VERSION 5.7 ;
BUSBITCHARS "[]" ;
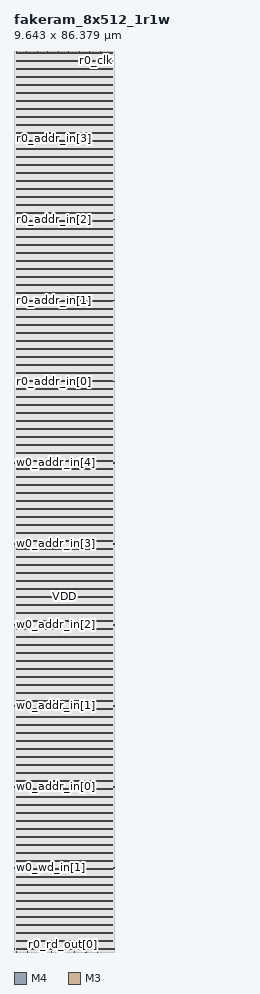
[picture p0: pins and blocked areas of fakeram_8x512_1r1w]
MACRO fakeram_8x512_1r1w
  FOREIGN fakeram_8x512_1r1w 0 0 ;
  SYMMETRY X Y R90 ;
  SIZE 9.643 BY 86.379 ;
  CLASS BLOCK ;
  PIN w0_wd_in[0]
    DIRECTION INPUT ;
    USE SIGNAL ;
    SHAPE ABUTMENT ;
    PORT
      LAYER M4 ;
      RECT 0.000 0.276 0.072 0.300 ;
    END
  END w0_wd_in[0]
  PIN w0_wd_in[1]
    DIRECTION INPUT ;
    USE SIGNAL ;
    SHAPE ABUTMENT ;
    PORT
      LAYER M4 ;
      RECT 0.000 8.052 0.072 8.076 ;
    END
  END w0_wd_in[1]
  PIN w0_wd_in[2]
    DIRECTION INPUT ;
    USE SIGNAL ;
    SHAPE ABUTMENT ;
    PORT
      LAYER M4 ;
      RECT 9.571 0.276 9.643 0.300 ;
    END
  END w0_wd_in[2]
  PIN w0_wd_in[3]
    DIRECTION INPUT ;
    USE SIGNAL ;
    SHAPE ABUTMENT ;
    PORT
      LAYER M4 ;
      RECT 9.571 8.052 9.643 8.076 ;
    END
  END w0_wd_in[3]
  PIN w0_wd_in[4]
    DIRECTION OUTPUT ;
    USE SIGNAL ;
    SHAPE ABUTMENT ;
    PORT
      LAYER M3 ;
      RECT 0.207 0.000 0.225 0.054 ;
    END
  END w0_wd_in[4]
  PIN w0_wd_in[5]
    DIRECTION OUTPUT ;
    USE SIGNAL ;
    SHAPE ABUTMENT ;
    PORT
      LAYER M3 ;
      RECT 1.323 0.000 1.341 0.054 ;
    END
  END w0_wd_in[5]
  PIN w0_wd_in[6]
    DIRECTION OUTPUT ;
    USE SIGNAL ;
    SHAPE ABUTMENT ;
    PORT
      LAYER M3 ;
      RECT 2.439 0.000 2.457 0.054 ;
    END
  END w0_wd_in[6]
  PIN w0_wd_in[7]
    DIRECTION OUTPUT ;
    USE SIGNAL ;
    SHAPE ABUTMENT ;
    PORT
      LAYER M3 ;
      RECT 3.555 0.000 3.573 0.054 ;
    END
  END w0_wd_in[7]
  PIN r0_rd_out[0]
    DIRECTION OUTPUT ;
    USE SIGNAL ;
    SHAPE ABUTMENT ;
    PORT
      LAYER M3 ;
      RECT 4.671 0.000 4.689 0.054 ;
    END
  END r0_rd_out[0]
  PIN r0_rd_out[1]
    DIRECTION OUTPUT ;
    USE SIGNAL ;
    SHAPE ABUTMENT ;
    PORT
      LAYER M3 ;
      RECT 5.787 0.000 5.805 0.054 ;
    END
  END r0_rd_out[1]
  PIN r0_rd_out[2]
    DIRECTION OUTPUT ;
    USE SIGNAL ;
    SHAPE ABUTMENT ;
    PORT
      LAYER M3 ;
      RECT 6.903 0.000 6.921 0.054 ;
    END
  END r0_rd_out[2]
  PIN r0_rd_out[3]
    DIRECTION OUTPUT ;
    USE SIGNAL ;
    SHAPE ABUTMENT ;
    PORT
      LAYER M3 ;
      RECT 8.019 0.000 8.037 0.054 ;
    END
  END r0_rd_out[3]
  PIN r0_rd_out[4]
    DIRECTION OUTPUT ;
    USE SIGNAL ;
    SHAPE ABUTMENT ;
    PORT
      LAYER M3 ;
      RECT 0.207 86.325 0.225 86.379 ;
    END
  END r0_rd_out[4]
  PIN r0_rd_out[5]
    DIRECTION OUTPUT ;
    USE SIGNAL ;
    SHAPE ABUTMENT ;
    PORT
      LAYER M3 ;
      RECT 1.215 86.325 1.233 86.379 ;
    END
  END r0_rd_out[5]
  PIN r0_rd_out[6]
    DIRECTION OUTPUT ;
    USE SIGNAL ;
    SHAPE ABUTMENT ;
    PORT
      LAYER M3 ;
      RECT 2.223 86.325 2.241 86.379 ;
    END
  END r0_rd_out[6]
  PIN r0_rd_out[7]
    DIRECTION OUTPUT ;
    USE SIGNAL ;
    SHAPE ABUTMENT ;
    PORT
      LAYER M3 ;
      RECT 3.231 86.325 3.249 86.379 ;
    END
  END r0_rd_out[7]
  PIN w0_addr_in[0]
    DIRECTION INPUT ;
    USE SIGNAL ;
    SHAPE ABUTMENT ;
    PORT
      LAYER M4 ;
      RECT 0.000 15.828 0.072 15.852 ;
    END
  END w0_addr_in[0]
  PIN w0_addr_in[1]
    DIRECTION INPUT ;
    USE SIGNAL ;
    SHAPE ABUTMENT ;
    PORT
      LAYER M4 ;
      RECT 0.000 23.604 0.072 23.628 ;
    END
  END w0_addr_in[1]
  PIN w0_addr_in[2]
    DIRECTION INPUT ;
    USE SIGNAL ;
    SHAPE ABUTMENT ;
    PORT
      LAYER M4 ;
      RECT 0.000 31.380 0.072 31.404 ;
    END
  END w0_addr_in[2]
  PIN w0_addr_in[3]
    DIRECTION INPUT ;
    USE SIGNAL ;
    SHAPE ABUTMENT ;
    PORT
      LAYER M4 ;
      RECT 0.000 39.156 0.072 39.180 ;
    END
  END w0_addr_in[3]
  PIN w0_addr_in[4]
    DIRECTION INPUT ;
    USE SIGNAL ;
    SHAPE ABUTMENT ;
    PORT
      LAYER M4 ;
      RECT 0.000 46.932 0.072 46.956 ;
    END
  END w0_addr_in[4]
  PIN w0_addr_in[5]
    DIRECTION INPUT ;
    USE SIGNAL ;
    SHAPE ABUTMENT ;
    PORT
      LAYER M4 ;
      RECT 9.571 15.828 9.643 15.852 ;
    END
  END w0_addr_in[5]
  PIN w0_addr_in[6]
    DIRECTION INPUT ;
    USE SIGNAL ;
    SHAPE ABUTMENT ;
    PORT
      LAYER M4 ;
      RECT 9.571 23.604 9.643 23.628 ;
    END
  END w0_addr_in[6]
  PIN w0_addr_in[7]
    DIRECTION INPUT ;
    USE SIGNAL ;
    SHAPE ABUTMENT ;
    PORT
      LAYER M4 ;
      RECT 9.571 31.380 9.643 31.404 ;
    END
  END w0_addr_in[7]
  PIN w0_addr_in[8]
    DIRECTION INPUT ;
    USE SIGNAL ;
    SHAPE ABUTMENT ;
    PORT
      LAYER M4 ;
      RECT 9.571 39.156 9.643 39.180 ;
    END
  END w0_addr_in[8]
  PIN r0_addr_in[0]
    DIRECTION INPUT ;
    USE SIGNAL ;
    SHAPE ABUTMENT ;
    PORT
      LAYER M4 ;
      RECT 0.000 54.708 0.072 54.732 ;
    END
  END r0_addr_in[0]
  PIN r0_addr_in[1]
    DIRECTION INPUT ;
    USE SIGNAL ;
    SHAPE ABUTMENT ;
    PORT
      LAYER M4 ;
      RECT 0.000 62.484 0.072 62.508 ;
    END
  END r0_addr_in[1]
  PIN r0_addr_in[2]
    DIRECTION INPUT ;
    USE SIGNAL ;
    SHAPE ABUTMENT ;
    PORT
      LAYER M4 ;
      RECT 0.000 70.260 0.072 70.284 ;
    END
  END r0_addr_in[2]
  PIN r0_addr_in[3]
    DIRECTION INPUT ;
    USE SIGNAL ;
    SHAPE ABUTMENT ;
    PORT
      LAYER M4 ;
      RECT 0.000 78.036 0.072 78.060 ;
    END
  END r0_addr_in[3]
  PIN r0_addr_in[4]
    DIRECTION INPUT ;
    USE SIGNAL ;
    SHAPE ABUTMENT ;
    PORT
      LAYER M4 ;
      RECT 0.000 85.812 0.072 85.836 ;
    END
  END r0_addr_in[4]
  PIN r0_addr_in[5]
    DIRECTION INPUT ;
    USE SIGNAL ;
    SHAPE ABUTMENT ;
    PORT
      LAYER M4 ;
      RECT 9.571 46.932 9.643 46.956 ;
    END
  END r0_addr_in[5]
  PIN r0_addr_in[6]
    DIRECTION INPUT ;
    USE SIGNAL ;
    SHAPE ABUTMENT ;
    PORT
      LAYER M4 ;
      RECT 9.571 54.708 9.643 54.732 ;
    END
  END r0_addr_in[6]
  PIN r0_addr_in[7]
    DIRECTION INPUT ;
    USE SIGNAL ;
    SHAPE ABUTMENT ;
    PORT
      LAYER M4 ;
      RECT 9.571 62.484 9.643 62.508 ;
    END
  END r0_addr_in[7]
  PIN r0_addr_in[8]
    DIRECTION INPUT ;
    USE SIGNAL ;
    SHAPE ABUTMENT ;
    PORT
      LAYER M4 ;
      RECT 9.571 70.260 9.643 70.284 ;
    END
  END r0_addr_in[8]
  PIN w0_we_in
    DIRECTION INPUT ;
    USE SIGNAL ;
    SHAPE ABUTMENT ;
    PORT
      LAYER M3 ;
      RECT 4.239 86.325 4.257 86.379 ;
    END
  END w0_we_in
  PIN w0_ce_in
    DIRECTION INPUT ;
    USE SIGNAL ;
    SHAPE ABUTMENT ;
    PORT
      LAYER M3 ;
      RECT 5.247 86.325 5.265 86.379 ;
    END
  END w0_ce_in
  PIN w0_clk
    DIRECTION INPUT ;
    USE SIGNAL ;
    SHAPE ABUTMENT ;
    PORT
      LAYER M3 ;
      RECT 6.255 86.325 6.273 86.379 ;
    END
  END w0_clk
  PIN r0_ce_in
    DIRECTION INPUT ;
    USE SIGNAL ;
    SHAPE ABUTMENT ;
    PORT
      LAYER M3 ;
      RECT 7.263 86.325 7.281 86.379 ;
    END
  END r0_ce_in
  PIN r0_clk
    DIRECTION INPUT ;
    USE SIGNAL ;
    SHAPE ABUTMENT ;
    PORT
      LAYER M3 ;
      RECT 8.271 86.325 8.289 86.379 ;
    END
  END r0_clk
  PIN VSS
    DIRECTION INOUT ;
    USE GROUND ;
    PORT
      LAYER M4 ;
      RECT 0.216 0.240 9.427 0.336 ;
      RECT 0.216 1.008 9.427 1.104 ;
      RECT 0.216 1.776 9.427 1.872 ;
      RECT 0.216 2.544 9.427 2.640 ;
      RECT 0.216 3.312 9.427 3.408 ;
      RECT 0.216 4.080 9.427 4.176 ;
      RECT 0.216 4.848 9.427 4.944 ;
      RECT 0.216 5.616 9.427 5.712 ;
      RECT 0.216 6.384 9.427 6.480 ;
      RECT 0.216 7.152 9.427 7.248 ;
      RECT 0.216 7.920 9.427 8.016 ;
      RECT 0.216 8.688 9.427 8.784 ;
      RECT 0.216 9.456 9.427 9.552 ;
      RECT 0.216 10.224 9.427 10.320 ;
      RECT 0.216 10.992 9.427 11.088 ;
      RECT 0.216 11.760 9.427 11.856 ;
      RECT 0.216 12.528 9.427 12.624 ;
      RECT 0.216 13.296 9.427 13.392 ;
      RECT 0.216 14.064 9.427 14.160 ;
      RECT 0.216 14.832 9.427 14.928 ;
      RECT 0.216 15.600 9.427 15.696 ;
      RECT 0.216 16.368 9.427 16.464 ;
      RECT 0.216 17.136 9.427 17.232 ;
      RECT 0.216 17.904 9.427 18.000 ;
      RECT 0.216 18.672 9.427 18.768 ;
      RECT 0.216 19.440 9.427 19.536 ;
      RECT 0.216 20.208 9.427 20.304 ;
      RECT 0.216 20.976 9.427 21.072 ;
      RECT 0.216 21.744 9.427 21.840 ;
      RECT 0.216 22.512 9.427 22.608 ;
      RECT 0.216 23.280 9.427 23.376 ;
      RECT 0.216 24.048 9.427 24.144 ;
      RECT 0.216 24.816 9.427 24.912 ;
      RECT 0.216 25.584 9.427 25.680 ;
      RECT 0.216 26.352 9.427 26.448 ;
      RECT 0.216 27.120 9.427 27.216 ;
      RECT 0.216 27.888 9.427 27.984 ;
      RECT 0.216 28.656 9.427 28.752 ;
      RECT 0.216 29.424 9.427 29.520 ;
      RECT 0.216 30.192 9.427 30.288 ;
      RECT 0.216 30.960 9.427 31.056 ;
      RECT 0.216 31.728 9.427 31.824 ;
      RECT 0.216 32.496 9.427 32.592 ;
      RECT 0.216 33.264 9.427 33.360 ;
      RECT 0.216 34.032 9.427 34.128 ;
      RECT 0.216 34.800 9.427 34.896 ;
      RECT 0.216 35.568 9.427 35.664 ;
      RECT 0.216 36.336 9.427 36.432 ;
      RECT 0.216 37.104 9.427 37.200 ;
      RECT 0.216 37.872 9.427 37.968 ;
      RECT 0.216 38.640 9.427 38.736 ;
      RECT 0.216 39.408 9.427 39.504 ;
      RECT 0.216 40.176 9.427 40.272 ;
      RECT 0.216 40.944 9.427 41.040 ;
      RECT 0.216 41.712 9.427 41.808 ;
      RECT 0.216 42.480 9.427 42.576 ;
      RECT 0.216 43.248 9.427 43.344 ;
      RECT 0.216 44.016 9.427 44.112 ;
      RECT 0.216 44.784 9.427 44.880 ;
      RECT 0.216 45.552 9.427 45.648 ;
      RECT 0.216 46.320 9.427 46.416 ;
      RECT 0.216 47.088 9.427 47.184 ;
      RECT 0.216 47.856 9.427 47.952 ;
      RECT 0.216 48.624 9.427 48.720 ;
      RECT 0.216 49.392 9.427 49.488 ;
      RECT 0.216 50.160 9.427 50.256 ;
      RECT 0.216 50.928 9.427 51.024 ;
      RECT 0.216 51.696 9.427 51.792 ;
      RECT 0.216 52.464 9.427 52.560 ;
      RECT 0.216 53.232 9.427 53.328 ;
      RECT 0.216 54.000 9.427 54.096 ;
      RECT 0.216 54.768 9.427 54.864 ;
      RECT 0.216 55.536 9.427 55.632 ;
      RECT 0.216 56.304 9.427 56.400 ;
      RECT 0.216 57.072 9.427 57.168 ;
      RECT 0.216 57.840 9.427 57.936 ;
      RECT 0.216 58.608 9.427 58.704 ;
      RECT 0.216 59.376 9.427 59.472 ;
      RECT 0.216 60.144 9.427 60.240 ;
      RECT 0.216 60.912 9.427 61.008 ;
      RECT 0.216 61.680 9.427 61.776 ;
      RECT 0.216 62.448 9.427 62.544 ;
      RECT 0.216 63.216 9.427 63.312 ;
      RECT 0.216 63.984 9.427 64.080 ;
      RECT 0.216 64.752 9.427 64.848 ;
      RECT 0.216 65.520 9.427 65.616 ;
      RECT 0.216 66.288 9.427 66.384 ;
      RECT 0.216 67.056 9.427 67.152 ;
      RECT 0.216 67.824 9.427 67.920 ;
      RECT 0.216 68.592 9.427 68.688 ;
      RECT 0.216 69.360 9.427 69.456 ;
      RECT 0.216 70.128 9.427 70.224 ;
      RECT 0.216 70.896 9.427 70.992 ;
      RECT 0.216 71.664 9.427 71.760 ;
      RECT 0.216 72.432 9.427 72.528 ;
      RECT 0.216 73.200 9.427 73.296 ;
      RECT 0.216 73.968 9.427 74.064 ;
      RECT 0.216 74.736 9.427 74.832 ;
      RECT 0.216 75.504 9.427 75.600 ;
      RECT 0.216 76.272 9.427 76.368 ;
      RECT 0.216 77.040 9.427 77.136 ;
      RECT 0.216 77.808 9.427 77.904 ;
      RECT 0.216 78.576 9.427 78.672 ;
      RECT 0.216 79.344 9.427 79.440 ;
      RECT 0.216 80.112 9.427 80.208 ;
      RECT 0.216 80.880 9.427 80.976 ;
      RECT 0.216 81.648 9.427 81.744 ;
      RECT 0.216 82.416 9.427 82.512 ;
      RECT 0.216 83.184 9.427 83.280 ;
      RECT 0.216 83.952 9.427 84.048 ;
      RECT 0.216 84.720 9.427 84.816 ;
      RECT 0.216 85.488 9.427 85.584 ;
      RECT 0.216 86.256 9.427 86.352 ;
    END
  END VSS
  PIN VDD
    DIRECTION INOUT ;
    USE POWER ;
    PORT
      LAYER M4 ;
      RECT 0.216 0.240 9.427 0.336 ;
      RECT 0.216 1.008 9.427 1.104 ;
      RECT 0.216 1.776 9.427 1.872 ;
      RECT 0.216 2.544 9.427 2.640 ;
      RECT 0.216 3.312 9.427 3.408 ;
      RECT 0.216 4.080 9.427 4.176 ;
      RECT 0.216 4.848 9.427 4.944 ;
      RECT 0.216 5.616 9.427 5.712 ;
      RECT 0.216 6.384 9.427 6.480 ;
      RECT 0.216 7.152 9.427 7.248 ;
      RECT 0.216 7.920 9.427 8.016 ;
      RECT 0.216 8.688 9.427 8.784 ;
      RECT 0.216 9.456 9.427 9.552 ;
      RECT 0.216 10.224 9.427 10.320 ;
      RECT 0.216 10.992 9.427 11.088 ;
      RECT 0.216 11.760 9.427 11.856 ;
      RECT 0.216 12.528 9.427 12.624 ;
      RECT 0.216 13.296 9.427 13.392 ;
      RECT 0.216 14.064 9.427 14.160 ;
      RECT 0.216 14.832 9.427 14.928 ;
      RECT 0.216 15.600 9.427 15.696 ;
      RECT 0.216 16.368 9.427 16.464 ;
      RECT 0.216 17.136 9.427 17.232 ;
      RECT 0.216 17.904 9.427 18.000 ;
      RECT 0.216 18.672 9.427 18.768 ;
      RECT 0.216 19.440 9.427 19.536 ;
      RECT 0.216 20.208 9.427 20.304 ;
      RECT 0.216 20.976 9.427 21.072 ;
      RECT 0.216 21.744 9.427 21.840 ;
      RECT 0.216 22.512 9.427 22.608 ;
      RECT 0.216 23.280 9.427 23.376 ;
      RECT 0.216 24.048 9.427 24.144 ;
      RECT 0.216 24.816 9.427 24.912 ;
      RECT 0.216 25.584 9.427 25.680 ;
      RECT 0.216 26.352 9.427 26.448 ;
      RECT 0.216 27.120 9.427 27.216 ;
      RECT 0.216 27.888 9.427 27.984 ;
      RECT 0.216 28.656 9.427 28.752 ;
      RECT 0.216 29.424 9.427 29.520 ;
      RECT 0.216 30.192 9.427 30.288 ;
      RECT 0.216 30.960 9.427 31.056 ;
      RECT 0.216 31.728 9.427 31.824 ;
      RECT 0.216 32.496 9.427 32.592 ;
      RECT 0.216 33.264 9.427 33.360 ;
      RECT 0.216 34.032 9.427 34.128 ;
      RECT 0.216 34.800 9.427 34.896 ;
      RECT 0.216 35.568 9.427 35.664 ;
      RECT 0.216 36.336 9.427 36.432 ;
      RECT 0.216 37.104 9.427 37.200 ;
      RECT 0.216 37.872 9.427 37.968 ;
      RECT 0.216 38.640 9.427 38.736 ;
      RECT 0.216 39.408 9.427 39.504 ;
      RECT 0.216 40.176 9.427 40.272 ;
      RECT 0.216 40.944 9.427 41.040 ;
      RECT 0.216 41.712 9.427 41.808 ;
      RECT 0.216 42.480 9.427 42.576 ;
      RECT 0.216 43.248 9.427 43.344 ;
      RECT 0.216 44.016 9.427 44.112 ;
      RECT 0.216 44.784 9.427 44.880 ;
      RECT 0.216 45.552 9.427 45.648 ;
      RECT 0.216 46.320 9.427 46.416 ;
      RECT 0.216 47.088 9.427 47.184 ;
      RECT 0.216 47.856 9.427 47.952 ;
      RECT 0.216 48.624 9.427 48.720 ;
      RECT 0.216 49.392 9.427 49.488 ;
      RECT 0.216 50.160 9.427 50.256 ;
      RECT 0.216 50.928 9.427 51.024 ;
      RECT 0.216 51.696 9.427 51.792 ;
      RECT 0.216 52.464 9.427 52.560 ;
      RECT 0.216 53.232 9.427 53.328 ;
      RECT 0.216 54.000 9.427 54.096 ;
      RECT 0.216 54.768 9.427 54.864 ;
      RECT 0.216 55.536 9.427 55.632 ;
      RECT 0.216 56.304 9.427 56.400 ;
      RECT 0.216 57.072 9.427 57.168 ;
      RECT 0.216 57.840 9.427 57.936 ;
      RECT 0.216 58.608 9.427 58.704 ;
      RECT 0.216 59.376 9.427 59.472 ;
      RECT 0.216 60.144 9.427 60.240 ;
      RECT 0.216 60.912 9.427 61.008 ;
      RECT 0.216 61.680 9.427 61.776 ;
      RECT 0.216 62.448 9.427 62.544 ;
      RECT 0.216 63.216 9.427 63.312 ;
      RECT 0.216 63.984 9.427 64.080 ;
      RECT 0.216 64.752 9.427 64.848 ;
      RECT 0.216 65.520 9.427 65.616 ;
      RECT 0.216 66.288 9.427 66.384 ;
      RECT 0.216 67.056 9.427 67.152 ;
      RECT 0.216 67.824 9.427 67.920 ;
      RECT 0.216 68.592 9.427 68.688 ;
      RECT 0.216 69.360 9.427 69.456 ;
      RECT 0.216 70.128 9.427 70.224 ;
      RECT 0.216 70.896 9.427 70.992 ;
      RECT 0.216 71.664 9.427 71.760 ;
      RECT 0.216 72.432 9.427 72.528 ;
      RECT 0.216 73.200 9.427 73.296 ;
      RECT 0.216 73.968 9.427 74.064 ;
      RECT 0.216 74.736 9.427 74.832 ;
      RECT 0.216 75.504 9.427 75.600 ;
      RECT 0.216 76.272 9.427 76.368 ;
      RECT 0.216 77.040 9.427 77.136 ;
      RECT 0.216 77.808 9.427 77.904 ;
      RECT 0.216 78.576 9.427 78.672 ;
      RECT 0.216 79.344 9.427 79.440 ;
      RECT 0.216 80.112 9.427 80.208 ;
      RECT 0.216 80.880 9.427 80.976 ;
      RECT 0.216 81.648 9.427 81.744 ;
      RECT 0.216 82.416 9.427 82.512 ;
      RECT 0.216 83.184 9.427 83.280 ;
      RECT 0.216 83.952 9.427 84.048 ;
      RECT 0.216 84.720 9.427 84.816 ;
      RECT 0.216 85.488 9.427 85.584 ;
      RECT 0.216 86.256 9.427 86.352 ;
    END
  END VDD
  OBS
    LAYER M1 ;
    RECT 0 0 9.643 86.379 ;
    LAYER M2 ;
    RECT 0 0 9.643 86.379 ;
    LAYER M3 ;
    RECT 0 0 9.643 86.379 ;
    LAYER M4 ;
    RECT 0 0 9.643 86.379 ;
  END
END fakeram_8x512_1r1w

END LIBRARY
